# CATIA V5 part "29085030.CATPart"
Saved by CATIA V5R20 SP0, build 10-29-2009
Part number: 29085030
Definition: NONE
Nomenclature: 29085030
Source: Unknown
Description: 29085030
Bounding box of the stored display mesh (mm): x -15 to 44.548, y -56.5 to 91.048, z -46.5 to 46.5
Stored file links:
  C:\Users\Utente\Desktop\IO LAVORO\3D X SITO CF\X SITO\PLASTICA\RF1\29085030.CATPart

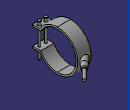
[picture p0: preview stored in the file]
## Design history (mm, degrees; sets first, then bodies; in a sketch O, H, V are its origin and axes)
Body1 "29085030" (main body)
  Solid1: solid without history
